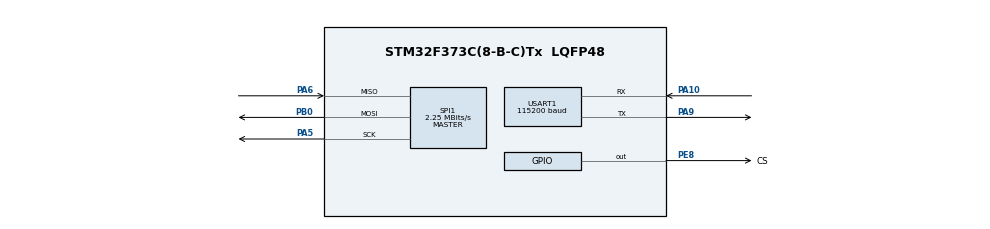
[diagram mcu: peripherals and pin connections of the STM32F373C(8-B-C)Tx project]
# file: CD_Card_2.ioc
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FATFS._USE_LABEL=1
FATFS._USE_LFN=3
Mcu.Family=STM32F3
Mcu.Name=STM32F373C(8-B-C)Tx
Mcu.Package=LQFP48
NVIC.PriorityGroup=NVIC_PRIORITYGROUP_4
PA10.Mode=Asynchronous
PA10.Signal=USART1_RX
PA13.Mode=Serial_Wire
PA13.Signal=SYS_JTMS-SWDIO
PA14.Mode=Serial_Wire
PA14.Signal=SYS_JTCK-SWCLK
PA5.Mode=Full_Duplex_Master
PA5.Signal=SPI1_SCK
PA6.GPIO_PuPd=GPIO_PULLUP
PA6.Mode=Full_Duplex_Master
PA6.Signal=SPI1_MISO
PA9.Mode=Asynchronous
PA9.Signal=USART1_TX
PB0.GPIO_PuPd=GPIO_PULLUP
PB0.Mode=Full_Duplex_Master
PB0.Signal=SPI1_MOSI
PE8.GPIO_Label=CS
PE8.GPIO_PuPd=GPIO_PULLUP
PE8.GPIO_Speed=GPIO_SPEED_FREQ_HIGH
PE8.PinState=GPIO_PIN_SET
PE8.Signal=GPIO_Output
PF0-OSC_IN.Mode=HSE-External-Oscillator
PF0-OSC_IN.Signal=RCC_OSC_IN
PF1-OSC_OUT.Mode=HSE-External-Oscillator
PF1-OSC_OUT.Signal=RCC_OSC_OUT
ProjectManager.HeapSize=0x200
ProjectManager.StackSize=0x400
ProjectManager.TargetToolchain=STM32CubeIDE
RCC.AHBFreq_Value=72000000
RCC.APB1CLKDivider=RCC_HCLK_DIV2
RCC.APB1Freq_Value=36000000
RCC.APB1TimFreq_Value=72000000
RCC.APB2Freq_Value=36000000
RCC.APB2TimFreq_Value=72000000
RCC.CortexFreq_Value=72000000
RCC.HCLKFreq_Value=72000000
RCC.HSE_VALUE=16000000
RCC.HSI_VALUE=8000000
RCC.LSE_VALUE=32768
RCC.PLLMUL=RCC_PLL_MUL9
RCC.PLLSourceVirtual=RCC_PLLSOURCE_HSE
RCC.RCC_PLLsource_Clock_Source_FROM_HSE=RCC_HSE_PREDIV_DIV2
RCC.SYSCLKFreq_VALUE=72000000
RCC.SYSCLKSource=RCC_SYSCLKSOURCE_PLLCLK
RCC.USBFreq_Value=72000000
SPI1.BaudRatePrescaler=SPI_BAUDRATEPRESCALER_16
SPI1.CalculateBaudRate=2.25 MBits/s
SPI1.Direction=SPI_DIRECTION_2LINES
SPI1.Mode=SPI_MODE_MASTER
SPI1.VirtualType=VM_MASTER
USART1.BaudRate=115200
USART1.VirtualMode-Asynchronous=VM_ASYNC
VP_FATFS_VS_Generic.Mode=User_defined
board=custom

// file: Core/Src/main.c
/* USER CODE BEGIN Header */
/**
  ******************************************************************************
  * @file           : main.c
  * @brief          : Main program body
  ******************************************************************************
  * @attention
  *
  * <h2><center>&copy; Copyright (c) 2026 STMicroelectronics.
  * All rights reserved.</center></h2>
  *
  * This software component is licensed by ST under BSD 3-Clause license,
  * the "License"; You may not use this file except in compliance with the
  * License. You may obtain a copy of the License at:
  *                        opensource.org/licenses/BSD-3-Clause
  *
  ******************************************************************************
  */
/* USER CODE END Header */
#include "main.h"
#include "fatfs.h"
#include "spi.h"
#include "usart.h"
#include "gpio.h"

/* USER CODE BEGIN Includes */
#include "sd_functions.h"
/* USER CODE END Includes */

void SystemClock_Config(void);

/* USER CODE BEGIN 0 */
int _write(int fd, unsigned char *buf, int len) {
  if (fd == 1 || fd == 2) {                     // stdout or stderr ?
    HAL_UART_Transmit(&huart1, buf, len, 999);  // Print to the UART
  }
  return len;
}
/* USER CODE END 0 */

int main(void)
{

  /* MCU Configuration--------------------------------------------------------*/

  /* Reset of all peripherals, Initializes the Flash interface and the Systick. */
  HAL_Init();

  /* Configure the system clock */
  SystemClock_Config();

  /* Initialize all configured peripherals */
  MX_GPIO_Init();
  MX_SPI1_Init();
  MX_USART1_UART_Init();
  /* USER CODE BEGIN 2 */
  HAL_Delay(10000);
  sd_mount();
  sd_list_files();
  sd_unmount();
  /* USER CODE END 2 */

  /* Infinite loop */
  while (1)
  {

  }
}

void SystemClock_Config(void)
{
  RCC_OscInitTypeDef RCC_OscInitStruct = {0};
  RCC_ClkInitTypeDef RCC_ClkInitStruct = {0};
  RCC_PeriphCLKInitTypeDef PeriphClkInit = {0};

  /** Initializes the RCC Oscillators according to the specified parameters
  * in the RCC_OscInitTypeDef structure.
  */
  RCC_OscInitStruct.OscillatorType = RCC_OSCILLATORTYPE_HSE;
  RCC_OscInitStruct.HSEState = RCC_HSE_ON;
  RCC_OscInitStruct.HSEPredivValue = RCC_HSE_PREDIV_DIV2;
  RCC_OscInitStruct.HSIState = RCC_HSI_ON;
  RCC_OscInitStruct.PLL.PLLState = RCC_PLL_ON;
  RCC_OscInitStruct.PLL.PLLSource = RCC_PLLSOURCE_HSE;
  RCC_OscInitStruct.PLL.PLLMUL = RCC_PLL_MUL9;
  if (HAL_RCC_OscConfig(&RCC_OscInitStruct) != HAL_OK)
  {
    Error_Handler();
  }
  /** Initializes the CPU, AHB and APB buses clocks
  */
  RCC_ClkInitStruct.ClockType = RCC_CLOCKTYPE_HCLK|RCC_CLOCKTYPE_SYSCLK
                              |RCC_CLOCKTYPE_PCLK1|RCC_CLOCKTYPE_PCLK2;
  RCC_ClkInitStruct.SYSCLKSource = RCC_SYSCLKSOURCE_PLLCLK;
  RCC_ClkInitStruct.AHBCLKDivider = RCC_SYSCLK_DIV1;
  RCC_ClkInitStruct.APB1CLKDivider = RCC_HCLK_DIV2;
  RCC_ClkInitStruct.APB2CLKDivider = RCC_HCLK_DIV1;

  if (HAL_RCC_ClockConfig(&RCC_ClkInitStruct, FLASH_LATENCY_2) != HAL_OK)
  {
    Error_Handler();
  }
  PeriphClkInit.PeriphClockSelection = RCC_PERIPHCLK_USART1;
  PeriphClkInit.Usart1ClockSelection = RCC_USART1CLKSOURCE_PCLK2;
  if (HAL_RCCEx_PeriphCLKConfig(&PeriphClkInit) != HAL_OK)
  {
    Error_Handler();
  }
}

void Error_Handler(void)
{
}

/************************ (C) COPYRIGHT STMicroelectronics *****END OF FILE****/
